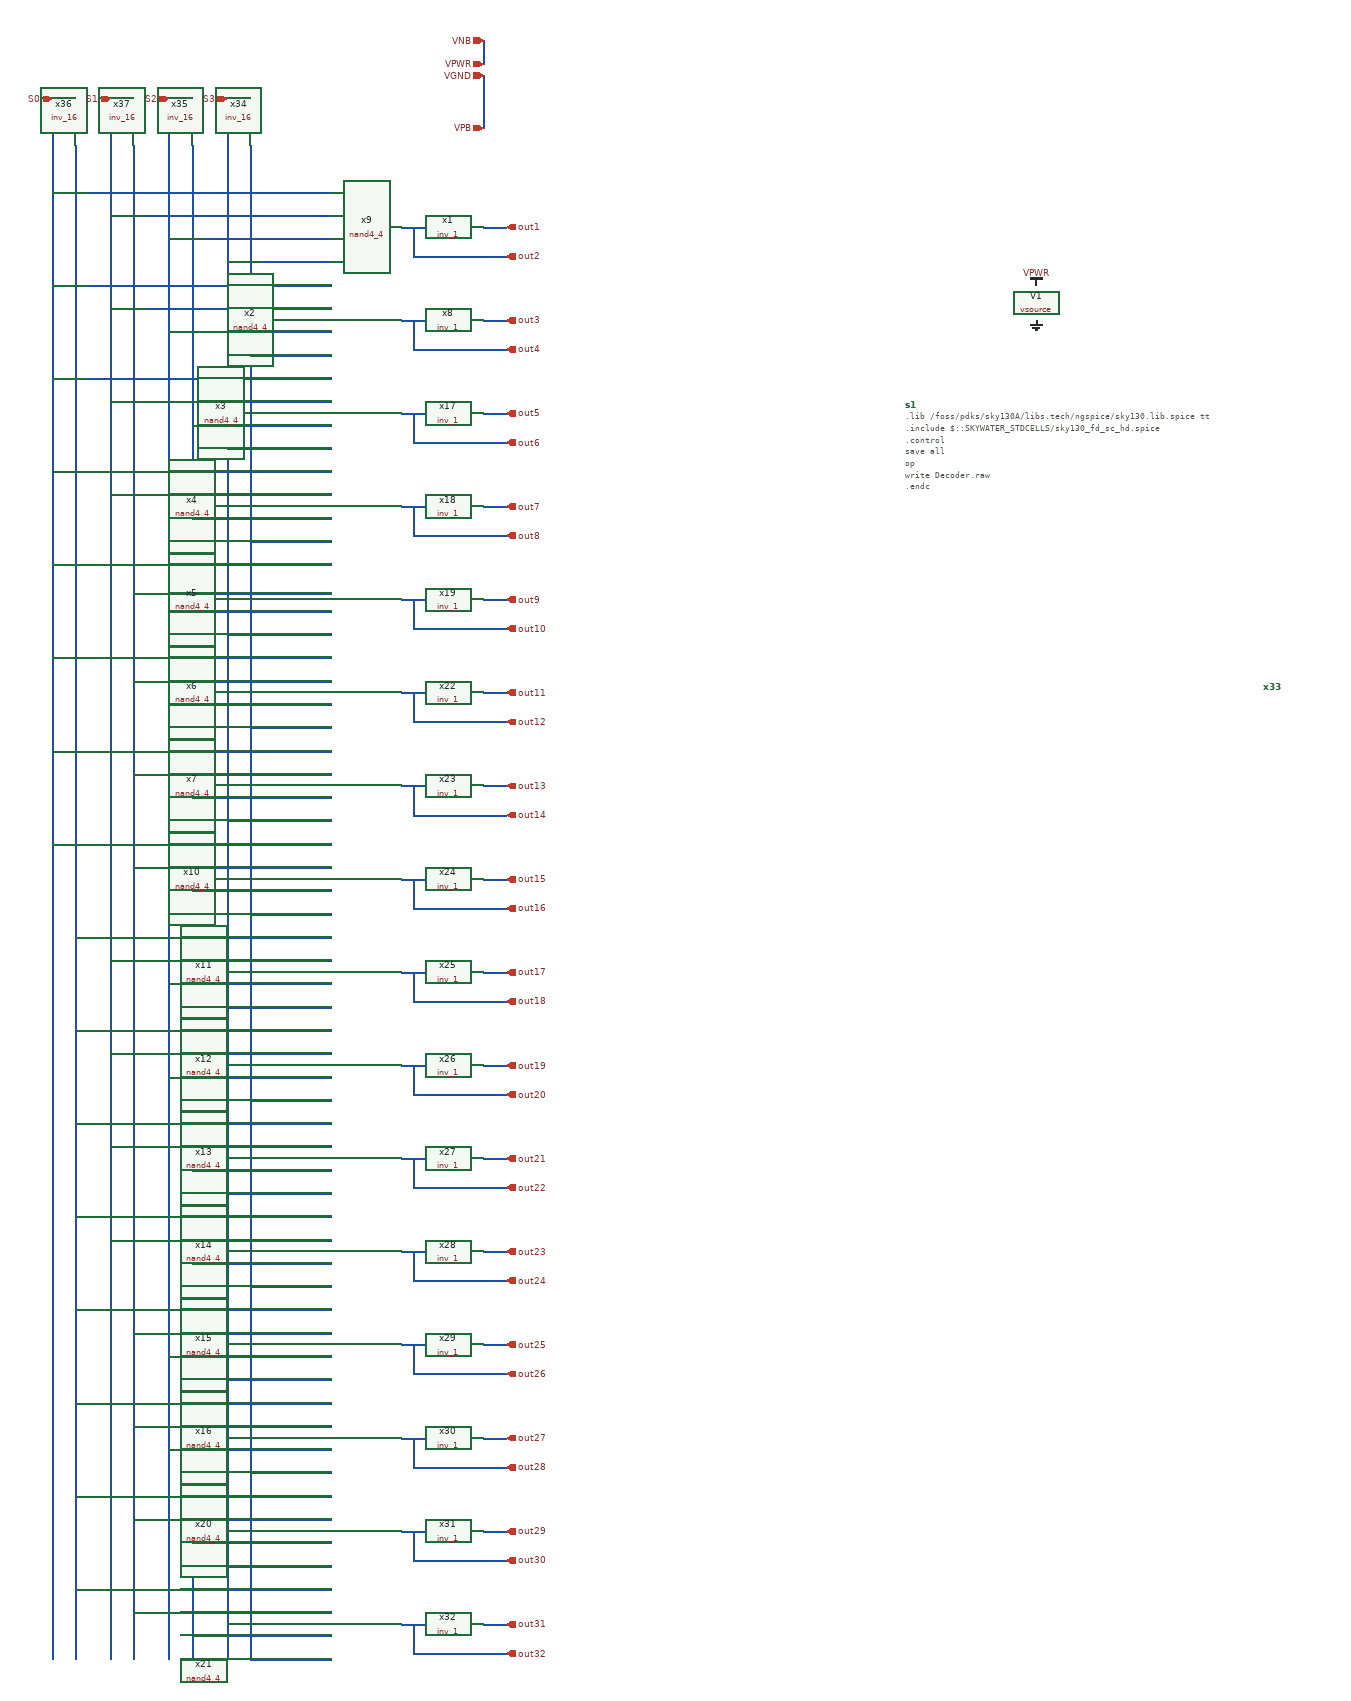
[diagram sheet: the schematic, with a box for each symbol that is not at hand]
v {xschem version=3.1.0 file_version=1.2
}
G {}
K {}
V {}
S {}
E {}
N 700 -2800 740 -2800 {
lab=S3}
N 700 -2800 700 -120 {
lab=S3}
N 600 -2800 600 -120 {
lab=S2}
N 500 -2800 500 -120 {
lab=S1}
N 400 -2800 400 -120 {
lab=S0}
N 600 -2800 640 -2800 {
lab=S2}
N 500 -2800 540 -2800 {
lab=S1}
N 400 -2800 440 -2800 {
lab=S0}
N 740 -2720 740 -120 {
lab=#net1}
N 640 -2720 640 -120 {
lab=#net2}
N 540 -2720 540 -120 {
lab=#net3}
N 440 -2720 440 -120 {
lab=#net4}
N 400 -2640 880 -2640 {
lab=S0}
N 500 -2600 880 -2600 {
lab=S1}
N 600 -2560 880 -2560 {
lab=S2}
N 700 -2520 880 -2520 {
lab=S3}
N 400 -2480 880 -2480 {
lab=S0}
N 400 -2320 880 -2320 {
lab=S0}
N 400 -2160 880 -2160 {
lab=S0}
N 400 -2000 880 -2000 {
lab=S0}
N 400 -1840 880 -1840 {
lab=S0}
N 400 -1680 880 -1680 {
lab=S0}
N 400 -1520 880 -1520 {
lab=S0}
N 500 -2440 880 -2440 {
lab=S1}
N 500 -2280 880 -2280 {
lab=S1}
N 500 -2120 880 -2120 {
lab=S1}
N 540 -1950 880 -1950 {
lab=#net3}
N 540 -1800 880 -1800 {
lab=#net3}
N 540 -1640 880 -1640 {
lab=#net3}
N 540 -1480 880 -1480 {
lab=#net3}
N 440 -1360 880 -1360 {
lab=#net4}
N 440 -1200 880 -1200 {
lab=#net4}
N 440 -1040 880 -1040 {
lab=#net4}
N 440 -880 880 -880 {
lab=#net4}
N 440 -720 880 -720 {
lab=#net4}
N 440 -560 880 -560 {
lab=#net4}
N 440 -400 880 -400 {
lab=#net4}
N 440 -240 880 -240 {
lab=#net4}
N 500 -1320 880 -1320 {
lab=S1}
N 500 -1160 880 -1160 {
lab=S1}
N 500 -1000 880 -1000 {
lab=S1}
N 500 -840 880 -840 {
lab=S1}
N 540 -680 880 -680 {
lab=#net3}
N 540 -520 880 -520 {
lab=#net3}
N 540 -360 880 -360 {
lab=#net3}
N 540 -200 880 -200 {
lab=#net3}
N 740 -2360 880 -2360 {
lab=#net1}
N 700 -2200 880 -2200 {
lab=S3}
N 740 -2040 880 -2040 {
lab=#net1}
N 700 -1880 880 -1880 {
lab=S3}
N 740 -1720 880 -1720 {
lab=#net1}
N 700 -1560 880 -1560 {
lab=S3}
N 740 -1400 880 -1400 {
lab=#net1}
N 700 -1240 880 -1240 {
lab=S3}
N 740 -1080 880 -1080 {
lab=#net1}
N 700 -920 880 -920 {
lab=S3}
N 740 -760 880 -760 {
lab=#net1}
N 700 -600 880 -600 {
lab=S3}
N 740 -440 880 -440 {
lab=#net1}
N 700 -280 880 -280 {
lab=S3}
N 740 -120 880 -120 {
lab=#net1}
N 600 -2400 880 -2400 {
lab=S2}
N 640 -2240 880 -2240 {
lab=#net2}
N 640 -2080 880 -2080 {
lab=#net2}
N 600 -1920 880 -1920 {
lab=S2}
N 600 -1760 880 -1760 {
lab=S2}
N 640 -1600 880 -1600 {
lab=#net2}
N 640 -1440 880 -1440 {
lab=#net2}
N 600 -1120 880 -1120 {
lab=S2}
N 640 -800 880 -800 {
lab=#net2}
N 600 -480 880 -480 {
lab=S2}
N 600 -1280 880 -1280 {
lab=S2}
N 640 -960 880 -960 {
lab=#net2}
N 600 -640 880 -640 {
lab=S2}
N 640 -320 880 -320 {
lab=#net2}
N 640 -160 880 -160 {
lab=#net2}
N 1140 -2900 1140 -2860 {
lab=VNB}
N 1140 -2840 1140 -2800 {
lab=VGND}
N 1140 -2800 1140 -2750 {
lab=VGND}
N 1000 -2580 1060 -2580 {
lab=out2}
N 1020 -2580 1060 -2580 {
lab=out2}
N 1020 -2580 1020 -2530 {
lab=out2}
N 1020 -2530 1180 -2530 {
lab=out2}
N 1140 -2580 1180 -2580 {
lab=out1}
N 1000 -2420 1060 -2420 {
lab=out4}
N 1020 -2420 1060 -2420 {
lab=out4}
N 1020 -2420 1020 -2370 {
lab=out4}
N 1020 -2370 1180 -2370 {
lab=out4}
N 1140 -2420 1180 -2420 {
lab=out3}
N 1000 -2260 1060 -2260 {
lab=out6}
N 1020 -2260 1060 -2260 {
lab=out6}
N 1020 -2260 1020 -2210 {
lab=out6}
N 1020 -2210 1180 -2210 {
lab=out6}
N 1140 -2260 1180 -2260 {
lab=out5}
N 1000 -2100 1060 -2100 {
lab=out8}
N 1020 -2100 1060 -2100 {
lab=out8}
N 1020 -2100 1020 -2050 {
lab=out8}
N 1020 -2050 1180 -2050 {
lab=out8}
N 1140 -2100 1180 -2100 {
lab=out7}
N 1000 -1940 1060 -1940 {
lab=out10}
N 1020 -1940 1060 -1940 {
lab=out10}
N 1020 -1940 1020 -1890 {
lab=out10}
N 1020 -1890 1180 -1890 {
lab=out10}
N 1140 -1940 1180 -1940 {
lab=out9}
N 1000 -1780 1060 -1780 {
lab=out12}
N 1020 -1780 1060 -1780 {
lab=out12}
N 1020 -1780 1020 -1730 {
lab=out12}
N 1020 -1730 1180 -1730 {
lab=out12}
N 1140 -1780 1180 -1780 {
lab=out11}
N 1000 -1620 1060 -1620 {
lab=out14}
N 1020 -1620 1060 -1620 {
lab=out14}
N 1020 -1620 1020 -1570 {
lab=out14}
N 1020 -1570 1180 -1570 {
lab=out14}
N 1140 -1620 1180 -1620 {
lab=out13}
N 1000 -1460 1060 -1460 {
lab=out16}
N 1020 -1460 1060 -1460 {
lab=out16}
N 1020 -1460 1020 -1410 {
lab=out16}
N 1020 -1410 1180 -1410 {
lab=out16}
N 1140 -1460 1180 -1460 {
lab=out15}
N 1000 -1300 1060 -1300 {
lab=out18}
N 1020 -1300 1060 -1300 {
lab=out18}
N 1020 -1300 1020 -1250 {
lab=out18}
N 1020 -1250 1180 -1250 {
lab=out18}
N 1140 -1300 1180 -1300 {
lab=out17}
N 1000 -1140 1060 -1140 {
lab=out20}
N 1020 -1140 1060 -1140 {
lab=out20}
N 1020 -1140 1020 -1090 {
lab=out20}
N 1020 -1090 1180 -1090 {
lab=out20}
N 1140 -1140 1180 -1140 {
lab=out19}
N 1000 -980 1060 -980 {
lab=out22}
N 1020 -980 1060 -980 {
lab=out22}
N 1020 -980 1020 -930 {
lab=out22}
N 1020 -930 1180 -930 {
lab=out22}
N 1140 -980 1180 -980 {
lab=out21}
N 1000 -820 1060 -820 {
lab=out24}
N 1020 -820 1060 -820 {
lab=out24}
N 1020 -820 1020 -770 {
lab=out24}
N 1020 -770 1180 -770 {
lab=out24}
N 1140 -820 1180 -820 {
lab=out23}
N 1000 -660 1060 -660 {
lab=out26}
N 1020 -660 1060 -660 {
lab=out26}
N 1020 -660 1020 -610 {
lab=out26}
N 1020 -610 1180 -610 {
lab=out26}
N 1140 -660 1180 -660 {
lab=out25}
N 1000 -500 1060 -500 {
lab=out28}
N 1020 -500 1060 -500 {
lab=out28}
N 1020 -500 1020 -450 {
lab=out28}
N 1020 -450 1180 -450 {
lab=out28}
N 1140 -500 1180 -500 {
lab=out27}
N 1000 -340 1060 -340 {
lab=out30}
N 1020 -340 1060 -340 {
lab=out30}
N 1020 -340 1020 -290 {
lab=out30}
N 1020 -290 1180 -290 {
lab=out30}
N 1140 -340 1180 -340 {
lab=out29}
N 1000 -180 1060 -180 {
lab=out32}
N 1020 -180 1060 -180 {
lab=out32}
N 1020 -180 1020 -130 {
lab=out32}
N 1020 -130 1180 -130 {
lab=out32}
N 1140 -180 1180 -180 {
lab=out31}
C {sky130_stdcells/inv_16.sym} 740 -2760 3 1 {name=x34 VGND=VGND VNB=VNB VPB=VPB VPWR=VPWR prefix=sky130_fd_sc_hd__ }
C {sky130_stdcells/inv_16.sym} 640 -2760 3 1 {name=x35 VGND=VGND VNB=VNB VPB=VPB VPWR=VPWR prefix=sky130_fd_sc_hd__ }
C {sky130_stdcells/inv_16.sym} 440 -2760 3 1 {name=x36 VGND=VGND VNB=VNB VPB=VPB VPWR=VPWR prefix=sky130_fd_sc_hd__ }
C {sky130_stdcells/inv_16.sym} 540 -2760 3 1 {name=x37 VGND=VGND VNB=VNB VPB=VPB VPWR=VPWR prefix=sky130_fd_sc_hd__ }
C {devices/ipin.sym} 400 -2800 0 0 {name=p9 lab=S0}
C {devices/ipin.sym} 500 -2800 0 0 {name=p10 lab=S1}
C {devices/ipin.sym} 600 -2800 0 0 {name=p35 lab=S2}
C {devices/ipin.sym} 700 -2800 0 0 {name=p36 lab=S3}
C {devices/vdd.sym} 2090 -2480 0 0 {name=l1 lab=VPWR}
C {devices/vsource.sym} 2090 -2450 0 0 {name=V1 value=1.8
}
C {devices/gnd.sym} 2090 -2420 0 0 {name=l2 lab=GND}
C {devices/code_shown.sym} 1865 -2275 0 0 {name=s1 only_toplevel=false value=
"
.lib /foss/pdks/sky130A/libs.tech/ngspice/sky130.lib.spice tt
.include $::SKYWATER_STDCELLS/sky130_fd_sc_hd.spice

.control
save all
op
write Decoder.raw
.endc
"}
C {devices/launcher.sym} 2040 -1930 0 0 {name=h1
descr=Annotate
tclcommand="xschem annotate_op"
}
C {devices/ipin.sym} 1140 -2840 0 0 {name=VGND lab=VGND}
C {devices/ipin.sym} 1140 -2900 0 0 {name=VNB lab=VNB}
C {devices/ipin.sym} 1140 -2750 0 0 {name=VPB lab=VPB}
C {devices/ipin.sym} 1140 -2860 0 0 {name=VPWR lab=VPWR}
C {sky130_stdcells/nand4_4.sym} 940 -2580 0 0 {name=x9 VGND=VGND VNB=VNB VPB=VPB VPWR=VPWR prefix=sky130_fd_sc_hd__ }
C {sky130_stdcells/nand4_4.sym} 940 -2420 0 0 {name=x2 VGND=VGND VNB=VNB VPB=VPB VPWR=VPWR prefix=sky130_fd_sc_hd__ }
C {sky130_stdcells/nand4_4.sym} 940 -2260 0 0 {name=x3 VGND=VGND VNB=VNB VPB=VPB VPWR=VPWR prefix=sky130_fd_sc_hd__ }
C {sky130_stdcells/nand4_4.sym} 940 -2100 0 0 {name=x4 VGND=VGND VNB=VNB VPB=VPB VPWR=VPWR prefix=sky130_fd_sc_hd__ }
C {sky130_stdcells/nand4_4.sym} 940 -1940 0 0 {name=x5 VGND=VGND VNB=VNB VPB=VPB VPWR=VPWR prefix=sky130_fd_sc_hd__ }
C {sky130_stdcells/nand4_4.sym} 940 -1780 0 0 {name=x6 VGND=VGND VNB=VNB VPB=VPB VPWR=VPWR prefix=sky130_fd_sc_hd__ }
C {sky130_stdcells/nand4_4.sym} 940 -1620 0 0 {name=x7 VGND=VGND VNB=VNB VPB=VPB VPWR=VPWR prefix=sky130_fd_sc_hd__ }
C {sky130_stdcells/nand4_4.sym} 940 -1460 0 0 {name=x10 VGND=VGND VNB=VNB VPB=VPB VPWR=VPWR prefix=sky130_fd_sc_hd__ }
C {sky130_stdcells/nand4_4.sym} 940 -1300 0 0 {name=x11 VGND=VGND VNB=VNB VPB=VPB VPWR=VPWR prefix=sky130_fd_sc_hd__ }
C {sky130_stdcells/nand4_4.sym} 940 -1140 0 0 {name=x12 VGND=VGND VNB=VNB VPB=VPB VPWR=VPWR prefix=sky130_fd_sc_hd__ }
C {sky130_stdcells/nand4_4.sym} 940 -980 0 0 {name=x13 VGND=VGND VNB=VNB VPB=VPB VPWR=VPWR prefix=sky130_fd_sc_hd__ }
C {sky130_stdcells/nand4_4.sym} 940 -820 0 0 {name=x14 VGND=VGND VNB=VNB VPB=VPB VPWR=VPWR prefix=sky130_fd_sc_hd__ }
C {sky130_stdcells/nand4_4.sym} 940 -660 0 0 {name=x15 VGND=VGND VNB=VNB VPB=VPB VPWR=VPWR prefix=sky130_fd_sc_hd__ }
C {sky130_stdcells/nand4_4.sym} 940 -500 0 0 {name=x16 VGND=VGND VNB=VNB VPB=VPB VPWR=VPWR prefix=sky130_fd_sc_hd__ }
C {sky130_stdcells/nand4_4.sym} 940 -340 0 0 {name=x20 VGND=VGND VNB=VNB VPB=VPB VPWR=VPWR prefix=sky130_fd_sc_hd__ }
C {sky130_stdcells/nand4_4.sym} 940 -180 0 0 {name=x21 VGND=VGND VNB=VNB VPB=VPB VPWR=VPWR prefix=sky130_fd_sc_hd__ }
C {sky130_stdcells/inv_1.sym} 1100 -2580 0 0 {name=x1 VGND=VGND VNB=VNB VPB=VPB VPWR=VPWR prefix=sky130_fd_sc_hd__ }
C {sky130_stdcells/inv_1.sym} 1100 -2420 0 0 {name=x8 VGND=VGND VNB=VNB VPB=VPB VPWR=VPWR prefix=sky130_fd_sc_hd__ }
C {sky130_stdcells/inv_1.sym} 1100 -2260 0 0 {name=x17 VGND=VGND VNB=VNB VPB=VPB VPWR=VPWR prefix=sky130_fd_sc_hd__ }
C {sky130_stdcells/inv_1.sym} 1100 -2100 0 0 {name=x18 VGND=VGND VNB=VNB VPB=VPB VPWR=VPWR prefix=sky130_fd_sc_hd__ }
C {sky130_stdcells/inv_1.sym} 1100 -1940 0 0 {name=x19 VGND=VGND VNB=VNB VPB=VPB VPWR=VPWR prefix=sky130_fd_sc_hd__ }
C {sky130_stdcells/inv_1.sym} 1100 -1780 0 0 {name=x22 VGND=VGND VNB=VNB VPB=VPB VPWR=VPWR prefix=sky130_fd_sc_hd__ }
C {sky130_stdcells/inv_1.sym} 1100 -1620 0 0 {name=x23 VGND=VGND VNB=VNB VPB=VPB VPWR=VPWR prefix=sky130_fd_sc_hd__ }
C {sky130_stdcells/inv_1.sym} 1100 -1460 0 0 {name=x24 VGND=VGND VNB=VNB VPB=VPB VPWR=VPWR prefix=sky130_fd_sc_hd__ }
C {sky130_stdcells/inv_1.sym} 1100 -1300 0 0 {name=x25 VGND=VGND VNB=VNB VPB=VPB VPWR=VPWR prefix=sky130_fd_sc_hd__ }
C {sky130_stdcells/inv_1.sym} 1100 -1140 0 0 {name=x26 VGND=VGND VNB=VNB VPB=VPB VPWR=VPWR prefix=sky130_fd_sc_hd__ }
C {sky130_stdcells/inv_1.sym} 1100 -980 0 0 {name=x27 VGND=VGND VNB=VNB VPB=VPB VPWR=VPWR prefix=sky130_fd_sc_hd__ }
C {sky130_stdcells/inv_1.sym} 1100 -820 0 0 {name=x28 VGND=VGND VNB=VNB VPB=VPB VPWR=VPWR prefix=sky130_fd_sc_hd__ }
C {sky130_stdcells/inv_1.sym} 1100 -660 0 0 {name=x29 VGND=VGND VNB=VNB VPB=VPB VPWR=VPWR prefix=sky130_fd_sc_hd__ }
C {sky130_stdcells/inv_1.sym} 1100 -500 0 0 {name=x30 VGND=VGND VNB=VNB VPB=VPB VPWR=VPWR prefix=sky130_fd_sc_hd__ }
C {sky130_stdcells/inv_1.sym} 1100 -340 0 0 {name=x31 VGND=VGND VNB=VNB VPB=VPB VPWR=VPWR prefix=sky130_fd_sc_hd__ }
C {sky130_stdcells/inv_1.sym} 1100 -180 0 0 {name=x32 VGND=VGND VNB=VNB VPB=VPB VPWR=VPWR prefix=sky130_fd_sc_hd__ }
C {devices/opin.sym} 1180 -2580 0 0 {name=p1 lab=out1}
C {devices/opin.sym} 1180 -2530 0 0 {name=p2 lab=out2}
C {devices/opin.sym} 1180 -2420 0 0 {name=p3 lab=out3}
C {devices/opin.sym} 1180 -2370 0 0 {name=p4 lab=out4}
C {devices/opin.sym} 1180 -2260 0 0 {name=p5 lab=out5}
C {devices/opin.sym} 1180 -2210 0 0 {name=p6 lab=out6}
C {devices/opin.sym} 1180 -2100 0 0 {name=p7 lab=out7}
C {devices/opin.sym} 1180 -2050 0 0 {name=p8 lab=out8}
C {devices/opin.sym} 1180 -1940 0 0 {name=p11 lab=out9}
C {devices/opin.sym} 1180 -1890 0 0 {name=p12 lab=out10}
C {devices/opin.sym} 1180 -1780 0 0 {name=p13 lab=out11}
C {devices/opin.sym} 1180 -1730 0 0 {name=p14 lab=out12}
C {devices/opin.sym} 1180 -1620 0 0 {name=p15 lab=out13}
C {devices/opin.sym} 1180 -1570 0 0 {name=p16 lab=out14}
C {devices/opin.sym} 1180 -1460 0 0 {name=p17 lab=out15}
C {devices/opin.sym} 1180 -1410 0 0 {name=p18 lab=out16}
C {devices/opin.sym} 1180 -1300 0 0 {name=p19 lab=out17}
C {devices/opin.sym} 1180 -1250 0 0 {name=p20 lab=out18}
C {devices/opin.sym} 1180 -1140 0 0 {name=p21 lab=out19}
C {devices/opin.sym} 1180 -1090 0 0 {name=p22 lab=out20}
C {devices/opin.sym} 1180 -980 0 0 {name=p23 lab=out21}
C {devices/opin.sym} 1180 -930 0 0 {name=p24 lab=out22}
C {devices/opin.sym} 1180 -820 0 0 {name=p25 lab=out23}
C {devices/opin.sym} 1180 -770 0 0 {name=p26 lab=out24}
C {devices/opin.sym} 1180 -660 0 0 {name=p27 lab=out25}
C {devices/opin.sym} 1180 -610 0 0 {name=p28 lab=out26}
C {devices/opin.sym} 1180 -500 0 0 {name=p29 lab=out27}
C {devices/opin.sym} 1180 -450 0 0 {name=p30 lab=out28}
C {devices/opin.sym} 1180 -340 0 0 {name=p31 lab=out29}
C {devices/opin.sym} 1180 -290 0 0 {name=p32 lab=out30}
C {devices/opin.sym} 1180 -180 0 0 {name=p33 lab=out31}
C {devices/opin.sym} 1180 -130 0 0 {name=p34 lab=out32}
C {Decoder.sym} 2480 -1790 0 0 {name=x33}
